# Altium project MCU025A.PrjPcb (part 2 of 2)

## Sheet MCU025A_XDS110_MCU.SchDoc
size 431 x 279 mm; Date: Not shown in title block; ApprovedBy: Not shown in title block; CheckedBy: Not shown in title block; Author: Not shown in title block; CompanyName: Not shown in title block; Engineer: Not shown in title block; Organization: Not shown in title block; Address1: Not shown in title block; Address2: Not shown in title block; Address3: Not shown in title block; Address4: Not shown in title block; DocumentNumber: 7; Revision: Use project parameter SCH_Rev; SheetNumber: 7; SheetTotal: 8; PageSetup: Record=PageOptions¦CenterHorizontal=True¦CenterVertical=True¦PrintScale=1.00¦XCorrection=1.00¦YCorrection=1.00¦PrintKind=0¦BorderSize=5000000¦LeftOffset=0¦BottomOffset=0¦Orientation=2¦PaperLength=1000¦PaperWidth=1000¦Scale=100¦PaperSource=15¦PrintQuality=600¦MediaType=1¦DitherType=10¦PaperKind=Letter¦PrintScaleMode=1

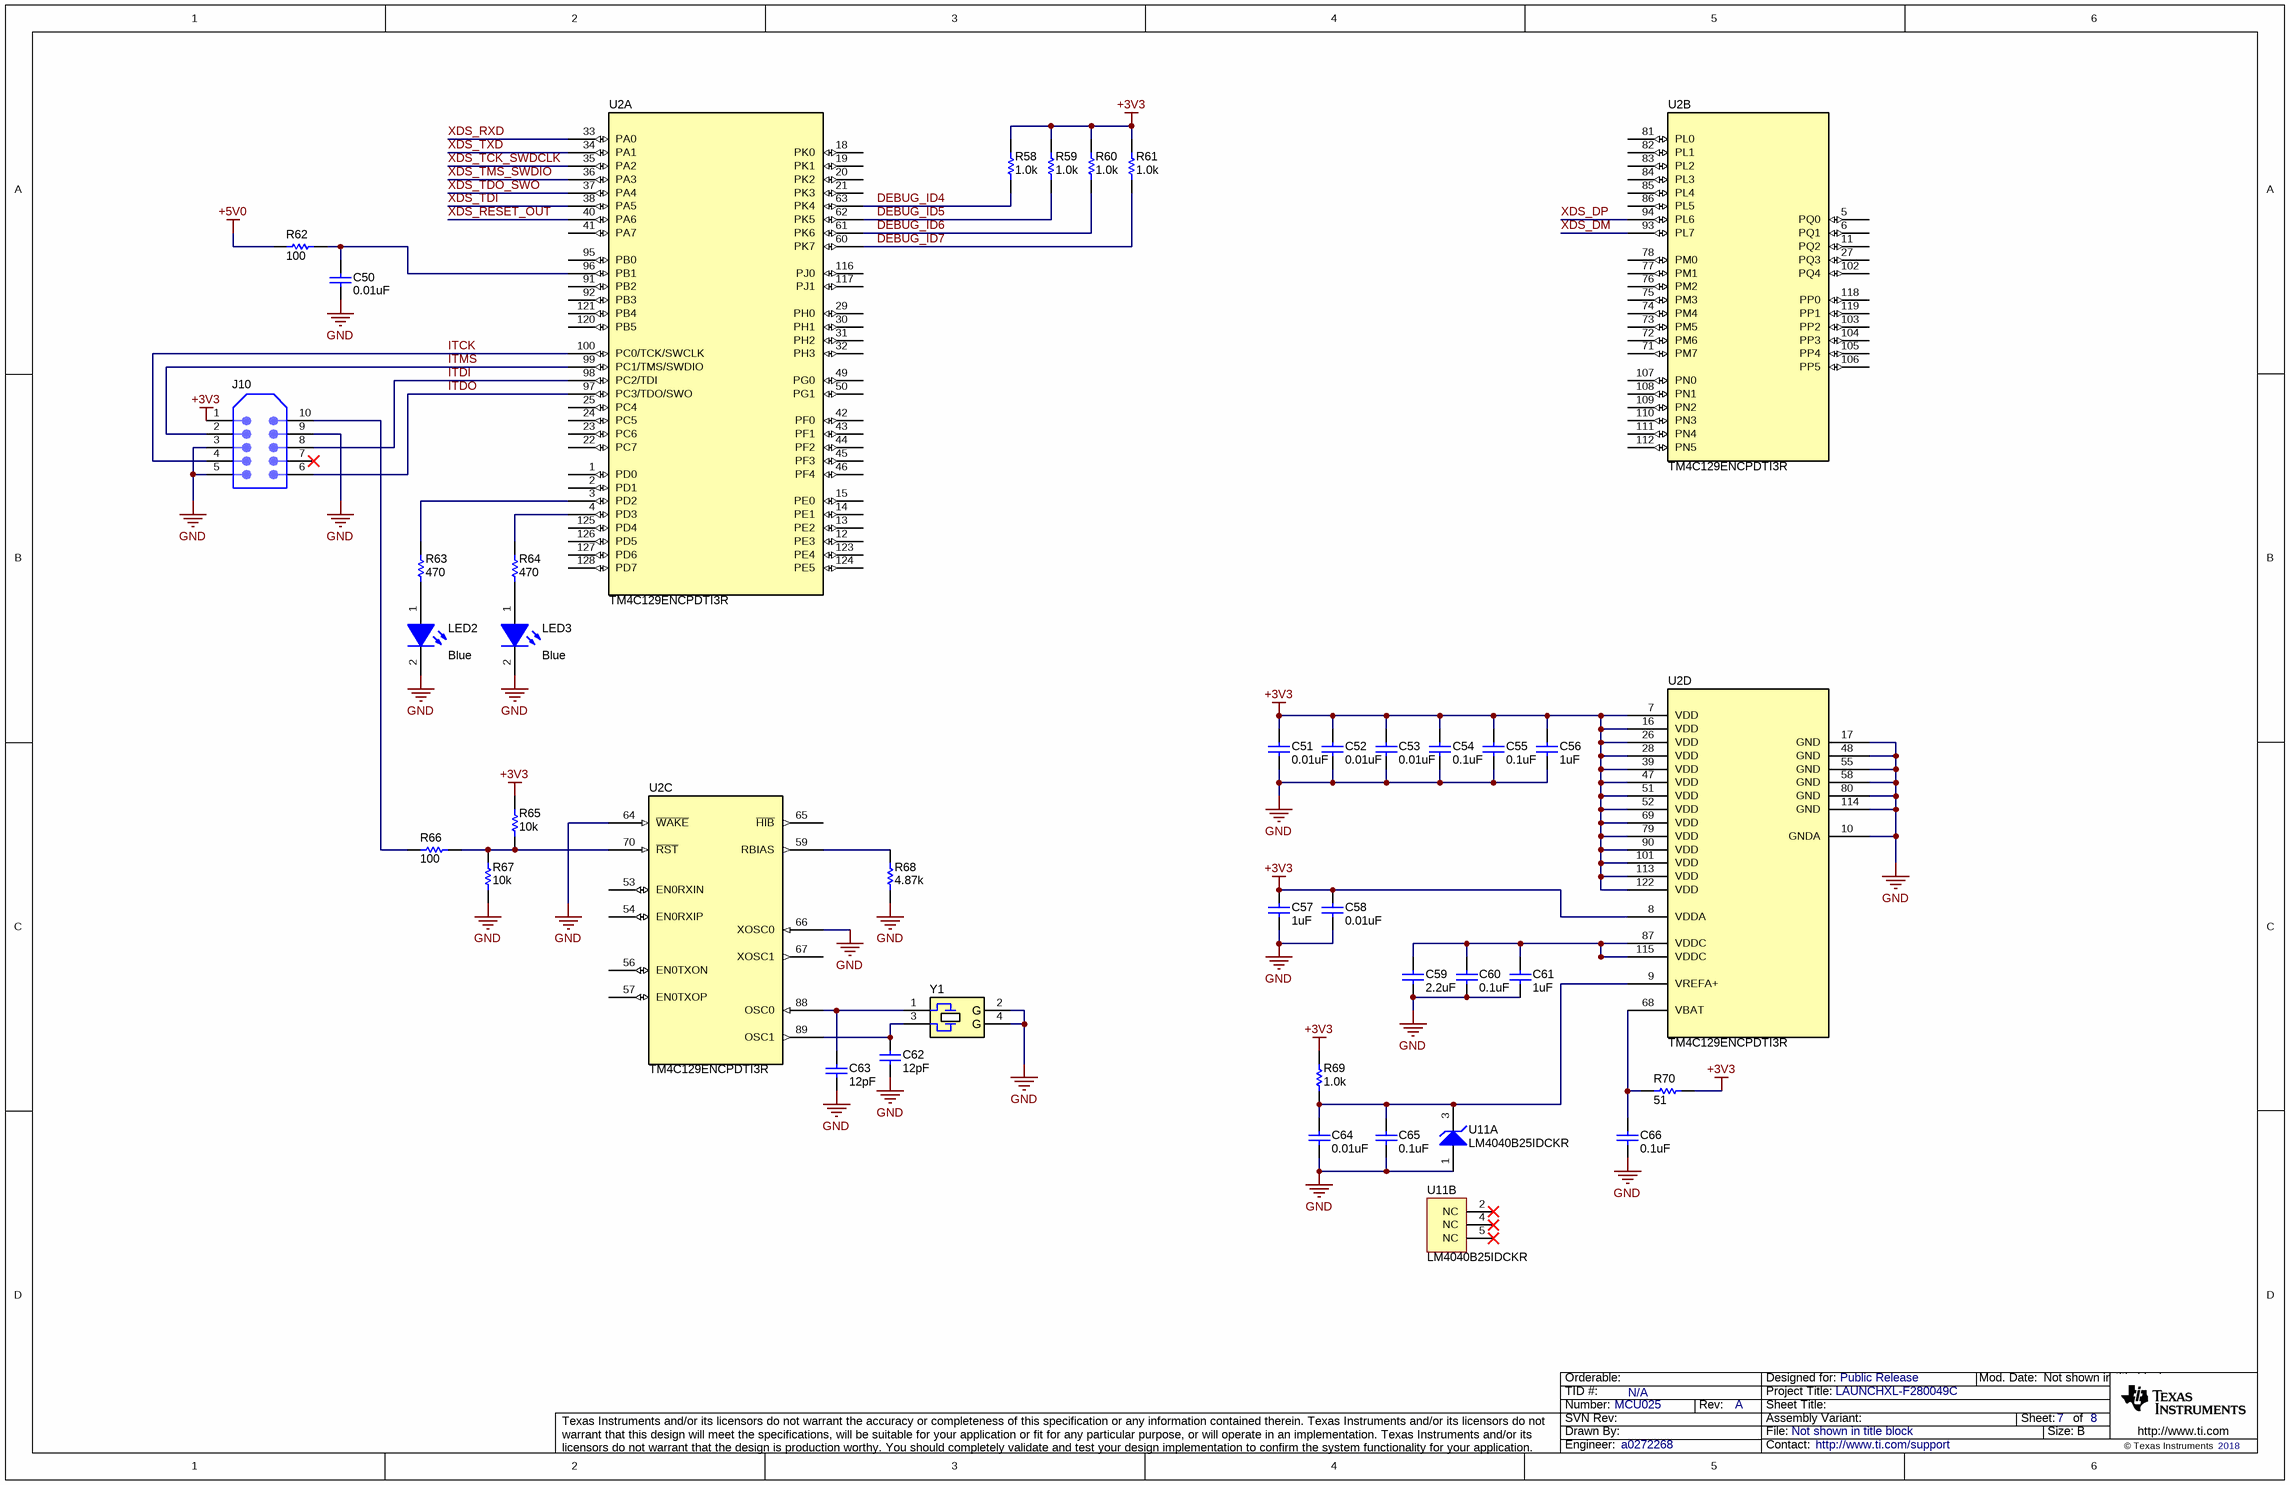
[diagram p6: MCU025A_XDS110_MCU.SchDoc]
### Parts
C50  ValueDisplayed: 0.01uF  [0402]  (hidden comment: GRM155R71E103KA01D)
C51  ValueDisplayed: 0.01uF  [0402]  (hidden comment: GRM155R71E103KA01D)
C52  ValueDisplayed: 0.01uF  [0402]  (hidden comment: GRM155R71E103KA01D)
C53  ValueDisplayed: 0.01uF  [0402]  (hidden comment: GRM155R71E103KA01D)
C54  ValueDisplayed: 0.1uF  [0402]  (hidden comment: GRM155R70J104KA01D)
C55  ValueDisplayed: 0.1uF  [0402]  (hidden comment: GRM155R70J104KA01D)
C56  ValueDisplayed: 1uF  [0402]  (hidden comment: GRM155R61A105KE15D)
C57  ValueDisplayed: 1uF  [0402]  (hidden comment: GRM155R61A105KE15D)
C58  ValueDisplayed: 0.01uF  [0402]  (hidden comment: GRM155R71E103KA01D)
C59  ValueDisplayed: 2.2uF  [0402]  (hidden comment: GRM155R60J225KE95D)
C60  ValueDisplayed: 0.1uF  [0402]  (hidden comment: GRM155R70J104KA01D)
C61  ValueDisplayed: 1uF  [0402]  (hidden comment: GRM155R61A105KE15D)
C62  ValueDisplayed: 12pF  [0402]  (hidden comment: GRM1555C1H120JA01D)
C63  ValueDisplayed: 12pF  [0402]  (hidden comment: GRM1555C1H120JA01D)
C64  ValueDisplayed: 0.01uF  [0402]  (hidden comment: GRM155R71E103KA01D)
C65  ValueDisplayed: 0.1uF  [0402]  (hidden comment: GRM155R70J104KA01D)
C66  ValueDisplayed: 0.1uF  [0402]  (hidden comment: GRM155R70J104KA01D)
J10  TC2050-IDC-NL-FP  [Tag_TC2050-NL]  (value not drawn)  (no BOM)
LED2  value Blue  [LTST-C170TBKT_Blue]  (hidden comment: LTST-C170TBKT)
LED3  value Blue  [LTST-C170TBKT_Blue]  (hidden comment: LTST-C170TBKT)
R58  ValueDisplayed: 1.0k  [0402]  (hidden comment: CRCW04021K00JNED)
R59  ValueDisplayed: 1.0k  [0402]  (hidden comment: CRCW04021K00JNED)
R60  ValueDisplayed: 1.0k  [0402]  (hidden comment: CRCW04021K00JNED)
R61  ValueDisplayed: 1.0k  [0402]  (hidden comment: CRCW04021K00JNED)
R62  ValueDisplayed: 100  [0402]  (hidden comment: CRCW0402100RJNED)
R63  ValueDisplayed: 470  [0402]  (hidden comment: ERJ-2RKF4700X)
R64  ValueDisplayed: 470  [0402]  (hidden comment: ERJ-2RKF4700X)
R65  ValueDisplayed: 10k  [0402]  (hidden comment: CRCW040210K0JNED)
R66  ValueDisplayed: 100  [0402]  (hidden comment: CRCW0402100RJNED)
R67  ValueDisplayed: 10k  [0402]  (hidden comment: CRCW040210K0JNED)
R68  ValueDisplayed: 4.87k  [0402]  (hidden comment: CRCW04024K87FKED)
R69  ValueDisplayed: 1.0k  [0402]  (hidden comment: CRCW04021K00JNED)
R70  ValueDisplayed: 51  [0402]  (hidden comment: CRCW040251R0JNED)
U2  TM4C129ENCPDTI3R  [PDT0128A]  (parts A,B,C,D of 4)
U11  LM4040B25IDCKR  [DCK0005A_N]  (parts A,B of 2)
Y1  NX3225GA-16.000M-STD-CRG-1  [NDK_NX3225GA]  (value not drawn)

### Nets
+3V3: C51.1 C52.1 C53.1 C54.1 C55.1 C56.1 C57.1 C58.1 J10.1 R58.2 R59.2 R60.2 R61.2 R65.2 R69.2 R70.2 U2.7(VDD) U2.8(VDDA) U2.16(VDD) U2.26(VDD) U2.28(VDD) U2.39(VDD) U2.47(VDD) U2.51(VDD) U2.52(VDD) U2.69(VDD) U2.79(VDD) U2.90(VDD) U2.101(VDD) U2.113(VDD) U2.122(VDD)
+5V0: R62.1
GND: C50.2 C51.2 C52.2 C53.2 C54.2 C55.2 C56.2 C57.2 C58.2 C59.2 C60.2 C61.2 C62.2 C63.2 C64.2 C65.2 C66.2 J10.3 J10.5 J10.9 LED2.2(K) LED3.2(K) R67.1 R68.1 U2.10(GNDA) U2.17(GND) U2.48(GND) U2.55(GND) U2.58(GND) U2.64(~{WAKE}) U2.66(XOSC0) U2.80(GND) U2.114(GND) U11.1(ANODE) Y1.2(GND) Y1.4(GND)
DEBUG_ID4: R58.1 U2.63(PK4)
DEBUG_ID5: R59.1 U2.62(PK5)
DEBUG_ID6: R60.1 U2.61(PK6)
DEBUG_ID7: R61.1 U2.60(PK7)
ITCK: J10.4 U2.100(PC0/TCK/SWCLK)
ITDI: J10.8 U2.98(PC2/TDI)
ITDO: J10.6 U2.97(PC3/TDO/SWO)
ITMS: J10.2 U2.99(PC1/TMS/SWDIO)
XDS_DM: U2.93(PL7)
XDS_DP: U2.94(PL6)
XDS_RESET_OUT: U2.40(PA6)
XDS_RXD: U2.33(PA0)
XDS_TCK_SWDCLK: U2.35(PA2)
XDS_TDI: U2.38(PA5)
XDS_TDO_SWO: U2.37(PA4)
XDS_TMS_SWDIO: U2.36(PA3)
XDS_TXD: U2.34(PA1)
NetC50_1: C50.1 R62.2 U2.96(PB1)
NetC59_1: C59.1 C60.1 C61.1 U2.87(VDDC) U2.115(VDDC)
NetC62_1: C62.1 U2.89(OSC1) Y1.3
NetC63_1: C63.1 U2.88(OSC0) Y1.1
NetC64_1: C64.1 C65.1 R69.1 U2.9(VREFA+) U11.3(CATHODE)
NetC66_1: C66.1 R70.1 U2.68(VBAT)
NetJ10_10: J10.10 R66.1
NetLED2_1: LED2.1(A) R63.1
NetLED3_1: LED3.1(A) R64.1
NetR63_2: R63.2 U2.3(PD2)
NetR64_2: R64.2 U2.4(PD3)
NetR65_1: R65.1 R66.2 R67.2 U2.70(~{RST})
NetR68_2: R68.2 U2.59(RBIAS)

Not connected (* = marked no-connect by the designer): J10 7*; U2 1(PD0) 2(PD1) 5(PQ0) 6(PQ1) 11(PQ2) 12(PE3) 13(PE2) 14(PE1) 15(PE0) 18(PK0) 19(PK1) 20(PK2) 21(PK3) 22(PC7) 23(PC6) 24(PC5) 25(PC4) 27(PQ3) 29(PH0) 30(PH1) 31(PH2) 32(PH3) 41(PA7) 42(PF0) 43(PF1) 44(PF2) 45(PF3) 46(PF4) 49(PG0) 50(PG1) 53(EN0RXIN) 54(EN0RXIP) 56(EN0TXON) 57(EN0TXOP) 65(~{HIB}) 67(XOSC1) 71(PM7) 72(PM6) 73(PM5) 74(PM4) 75(PM3) 76(PM2) 77(PM1) 78(PM0) 81(PL0) 82(PL1) 83(PL2) 84(PL3) 85(PL4) 86(PL5) 91(PB2) 92(PB3) 95(PB0) 102(PQ4) 103(PP2) 104(PP3) 105(PP4) 106(PP5) 107(PN0) 108(PN1) 109(PN2) 110(PN3) 111(PN4) 112(PN5) 116(PJ0) 117(PJ1) 118(PP0) 119(PP1) 120(PB5) 121(PB4) 123(PE4) 124(PE5) 125(PD4) 126(PD5) 127(PD6) 128(PD7); U11 2(NC)* 4(NC)* 5(NC)*

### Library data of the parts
C50-C53 C58 C64 = CMP-0006658-2: CAP, CERM, 0.01 uF, 25 V, +/- 10%, X7R, 0402; Manufacturer: MuRata; Polarized: N; Value: 0.01uF; U/M: EA; Cap_F: 10nF; Value1: Unknown; VDC_V: 25V; TaMin_C: -55°C; TaMax_C: 125°C; SizeArea_mm2: 0.5; SizeAreaWB_mm2: 3; SizeX_mm: 1; SizeZ_mm: 0.6; AEC Category: Q200
C54 C55 C60 C65 C66 = CMP-0006623-2: CAP, CERM, 0.1 uF, 6.3 V, +/- 10%, X7R, 0402; Manufacturer: MuRata; Polarized: N; Value: 0.1uF; U/M: EA; Cap_F: 100nF; Value1: Unknown; VDC_V: 6.3V; TaMin_C: -55°C; TaMax_C: 125°C; SizeArea_mm2: 0.5; SizeAreaWB_mm2: 3; SizeX_mm: 1; SizeZ_mm: 0.6; AEC Category: Q200
C56 C57 C61 = CMP-0006563-2: CAP, CERM, 1 uF, 10 V, +/- 10%, X5R, 0402; Manufacturer: MuRata; Polarized: N; Value: 1uF; U/M: EA; Cap_F: 1µF; Value1: Unknown; VDC_V: 10V; TaMin_C: -55°C; TaMax_C: 85°C; SizeArea_mm2: 0.5; SizeAreaWB_mm2: 3; SizeX_mm: 1; SizeZ_mm: 0.6; AEC Category: Q200
C59 = CMP-0006543-2: CAP, CERM, 2.2 uF, 6.3 V, +/- 10%, X5R, 0402; Manufacturer: MuRata; Polarized: N; Value: 2.2uF; U/M: EA; Cap_F: 2.2µF; Value1: Unknown; VDC_V: 6.3V; TaMin_C: -55°C; TaMax_C: 85°C; SizeArea_mm2: 0.5; SizeAreaWB_mm2: 3; SizeX_mm: 1; SizeZ_mm: 0.6; AEC Category: Q200
C62 C63 = CMP-0006415-2: CAP, CERM, 12 pF, 50 V, +/- 5%, C0G/NP0, 0402; Manufacturer: MuRata; Polarized: N; Value: 12pF; U/M: EA; Value1: Unknown; VDC_V: 50V; TaMin_C: -55°C; TaMax_C: 125°C; SizeArea_mm2: 0.5; SizeAreaWB_mm2: 3; SizeX_mm: 1; SizeZ_mm: 0.6; AEC Category: Q200
J10 = CMP-0075101-1: Footprint for Tag-Connect TC2050 No-Legs cables; CompType: Receptacle; Note: Footprint only, to mate with Tag-Connect TC2050 No-Legs cables; CNHeader: False
LED2 LED3 = CMP-0002889-1: LED, Blue, SMD; Manufacturer: Lite-On; Type: AlInGaP; Vf_V: 3.3V; Io_A: 20mA; Value1: W; U/M: EA
R58-R61 = CMP-0026852-3: RES, 1.0 k, 5%, 0.063 W, AEC-Q200 Grade 0, 0402; Manufacturer: Vishay-Dale; Power_W: 63mW; TempCo: 200 ppm/C; Value_Code: 1k00; Value: 1.0k; EIA_Code: E24; Res_ohm: 1k; SizeX_mm: 1; SizeY_mm: 0.5; SizeZ_mm: 0.6; Value2: 0.063W; AEC Qualified: Y; VDC_V: 50V; AEC Category: Q200; AEC Grade: 0
R62 R66 = CMP-0026824-3: RES, 100, 5%, 0.063 W, AEC-Q200 Grade 0, 0402; Manufacturer: Vishay-Dale; Value: 100; Value_Code: 100R; Power_W: 63mW; Value2: 0.063W; VDC_V: 50V; TempCo: 200 ppm/C; SizeArea_mm2: 0.5; SizeX_mm: 1; SizeZ_mm: 0.6; EIA_Code: E24; AEC Category: Q200; AEC Qualified: Y; AEC Grade: 0
R63 R64 = CMP-0026699-1: RES, 470, 1%, 0.1 W, AEC-Q200 Grade 0, 0402; Manufacturer: Panasonic; Value: 470; Value_Code: 470R; Power_W: 100mW; Value2: 0.1W; VDC_V: 50V; TempCo: 100 ppm/C; SizeArea_mm2: 0.5; SizeX_mm: 1; SizeZ_mm: 0.6; U/M: EA; AEC Category: Q200; AEC Qualified: Y; AEC Grade: 0
R65 R67 = CMP-0026825-5: RES, 10 k, 5%, 0.063 W, AEC-Q200 Grade 0, 0402; Manufacturer: Vishay-Dale; Value: 10k; Value_Code: 10k0; Power_W: 63mW; Value2: 0.063W; VDC_V: 50V; TempCo: 200 ppm/C; SizeArea_mm2: 0.5; SizeX_mm: 1; SizeZ_mm: 0.6; EIA_Code: E24; AEC Category: Q200; AEC Qualified: Y; AEC Grade: 0
R68 = CMP-0026413-2: RES, 4.87 k, 1%, 0.063 W, AEC-Q200 Grade 0, 0402; Manufacturer: Vishay-Dale; Value: 4.87k; Value_Code: 4k87; Power_W: 63mW; Value2: 0.063W; VDC_V: 50V; TempCo: 100 ppm/C; SizeArea_mm2: 0.5; SizeX_mm: 1; SizeZ_mm: 0.6; EIA_Code: E96; AEC Category: Q200; AEC Qualified: Y; AEC Grade: 0
R69 = CMP-0026852-3: RES, 1.0 k, 5%, 0.063 W, AEC-Q200 Grade 0, 0402; Manufacturer: Vishay-Dale; Value: 1.0k; Res_ohm: 1k; Value_Code: 1k00; Power_W: 63mW; Value2: 0.063W; VDC_V: 50V; TempCo: 200 ppm/C; SizeArea_mm2: 0.5; SizeX_mm: 1; SizeZ_mm: 0.6; EIA_Code: E24; AEC Category: Q200; AEC Qualified: Y; AEC Grade: 0
R70 = CMP-0026946-3: RES, 51, 5%, 0.063 W, AEC-Q200 Grade 0, 0402; Manufacturer: Vishay-Dale; Value: 51; Value_Code: 51R0; Power_W: 63mW; Value2: 0.063W; VDC_V: 50V; TempCo: 200 ppm/C; SizeArea_mm2: 0.5; SizeX_mm: 1; SizeZ_mm: 0.6; EIA_Code: E24; AEC Category: Q200; AEC Qualified: Y; AEC Grade: 0
U2 = CMP-0067512-2: IoT enabled High performance 32-bit ARM(R) Cortex(R)-M4F based MCU, PDT0128A (TQFP-128); Manufacturer: Texas Instruments; SizeArea_mm2: 256.0; SizeAreaWB_mm2: 324.0; SizeX_mm: 16.0; SizeZ_mm: 1.2; CompType: IC; U/M: EA
U11 = CMP-0032785-2: Precision Micropower Shunt Voltage Reference, 0.2% accuracy, 2.5 V, 15 ppm / degC, 15 mA, -40 to 85 degC, 5-pin SC70 (DCK), Green (RoHS & no Sb/Br); Manufacturer: Texas Instruments; Iout/Iz(Max)(mA): 15; Temp Coeff(Max)(ppm/ degree C): 100; VO(V): 2.5; Min Iz for Regulation(uA): 75; Initial Accuracy @ 25/deg C(%): 0.2; Rating: Catalog; AEC Category: Q200; AEC Qualified: N; CompType: IC; SizeArea_mm2: 4.2; SizeAreaWB_mm2: 9.3; SizeX_mm: 2.1; SizeY_mm: 2.0; SizeZ_mm: 1.1
Y1 = CMP-0004635-3: Crystal, 16 MHz, 8pF, SMD; Manufacturer: NDK; TaMin_C: -10°C; TaMax_C: 70°C; Frequency Stability: +/-30ppm; Frequency_Fixed: 16MHz

## Sheet MCU025A_Hardware.SchDoc
size 431 x 279 mm; Date: Not shown in title block; ApprovedBy: Not shown in title block; CheckedBy: Not shown in title block; Author: Not shown in title block; CompanyName: Not shown in title block; Engineer: Not shown in title block; Organization: Not shown in title block; Address1: Not shown in title block; Address2: Not shown in title block; Address3: Not shown in title block; Address4: Not shown in title block; DocumentNumber: 8; Revision: Use project parameter SCH_Rev; SheetNumber: 8; SheetTotal: 8; PageSetup: Record=PageOptions¦CenterHorizontal=True¦CenterVertical=True¦PrintScale=1.00¦XCorrection=1.00¦YCorrection=1.00¦PrintKind=0¦BorderSize=5000000¦LeftOffset=0¦BottomOffset=0¦Orientation=2¦PaperLength=1000¦PaperWidth=1000¦Scale=100¦PaperSource=15¦PrintQuality=600¦MediaType=1¦DitherType=10¦PaperKind=Letter¦PrintScaleMode=1

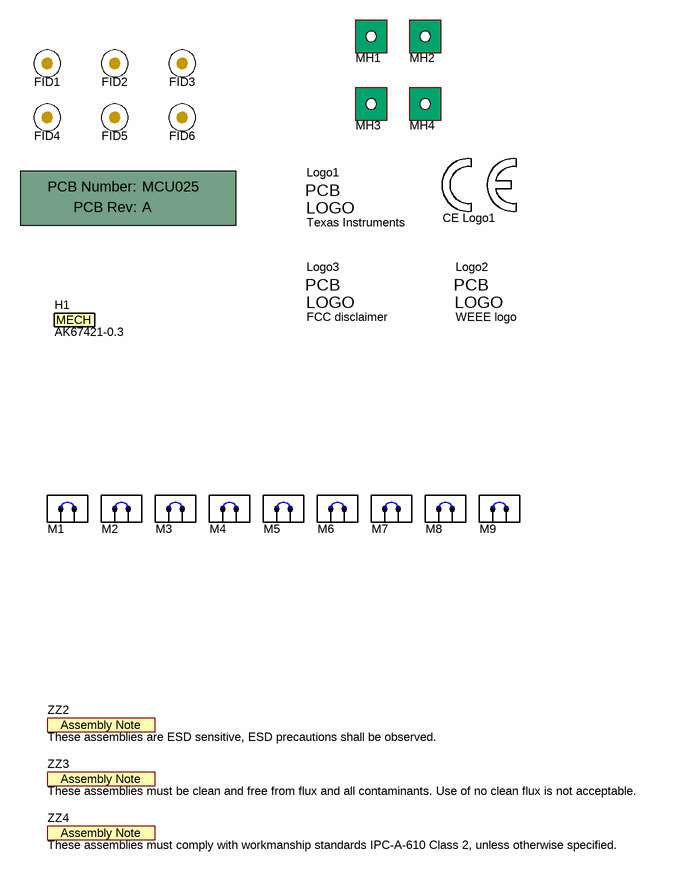
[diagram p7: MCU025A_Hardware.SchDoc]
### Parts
!PCB1  Printed Circuit Board  (value not drawn)  (mechanical)
CE_Logo1  CE Mark  [CE_Mark_5mm]  (value not drawn)  (no BOM)
FID1  Fiducial  [Fiducial10-20]  (value not drawn)  (no BOM)
FID2  Fiducial  [Fiducial10-20]  (value not drawn)  (no BOM)
FID3  Fiducial  [Fiducial10-20]  (value not drawn)  (no BOM)
FID4  Fiducial  [Fiducial10-20]  (value not drawn)  (no BOM)
FID5  Fiducial  [Fiducial10-20]  (value not drawn)  (no BOM)
FID6  Fiducial  [Fiducial10-20]  (value not drawn)  (no BOM)
H1  AK67421-0.3  (mechanical)
Logo1  Texas Instruments  [TI_Stacked_Overlay_Small]  (no BOM)
Logo2  WEEE logo  [WEEE_Minimum]  (no BOM)
Logo3  FCC disclaimer  [FCC_disclaimer]  (no BOM)
M1  60900213421  [Wurth_60900213421]  (value not drawn)
M2  60900213421  [Wurth_60900213421]  (value not drawn)
M3  60900213421  [Wurth_60900213421]  (value not drawn)
M4  60900213421  [Wurth_60900213421]  (value not drawn)
M5  60900213421  [Wurth_60900213421]  (value not drawn)
M6  60900213421  [Wurth_60900213421]  (value not drawn)
M7  60900213421  [Wurth_60900213421]  (value not drawn)
M8  60900213421  [Wurth_60900213421]  (value not drawn)
M9  60900213421  [Wurth_60900213421]  (value not drawn)
MH1  MTG_NoPads  [NPTH125mil]  (value not drawn)  (no BOM)
MH2  MTG_NoPads  [NPTH125mil]  (value not drawn)  (no BOM)
MH3  MTG_NoPads  [NPTH125mil]  (value not drawn)  (no BOM)
MH4  MTG_NoPads  [NPTH125mil]  (value not drawn)  (no BOM)
ZZ2  These assemblies are ESD sensitive, ESD precautions shall be observed.  [AssemblyNote]  (no BOM)
ZZ3  These assemblies must be clean and free from flux and all contaminants. Use of no clean flux is not acceptable.  [AssemblyNote]  (no BOM)
ZZ4  These assemblies must comply with workmanship standards IPC-A-610 Class 2, unless otherwise specified.  [AssemblyNote]  (no BOM)

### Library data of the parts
!PCB1 = CMP-0003618-2: Manufacturer: Any; PartNumber: MCU025
CE_Logo1 = CMP-0074844-1: SymbolCreator: a0412235
FID1-FID6 = CMP-0077181-1: Fiducial mark.  There is nothing to buy or mount.
H1 = CMP-0077983-1: Cable, USB-A to micro USB-B, 0.3 m; Manufacturer: Assman WSW
Logo1 = CMP-0074838-1: Texas Instrument Corporate Signature; SymbolCreator: a0412235; Lib Reference: TI_Logo; Library Reference: Logo
Logo2 = CMP-0074769-1
Logo3 = CMP-0074847-1: FCC_disclaimer; Library Reference: Logo
M1-M9 = CMP-0003761-2: Shunt, 2.54mm, Gold, Black; Manufacturer: Wurth Elektronik
MH1-MH4 = CMP-0078424-2: PCB Mounting Hole, No Pad; Manufacturer: Any; Key: Mounting Hole (non-standard) No Pad
ZZ2 = CMP-0077236-1
ZZ3 = CMP-0077237-1
ZZ4 = CMP-0077238-1

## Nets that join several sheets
+3V3: MCU025A_Connectors (5 pins), MCU025A_AltRouting_Misc (16 pins), MCU025A_F280049C_Device (6 pins), MCU025A_XDS110_Target_Interface (J102.1 R57.2 U12.8), MCU025A_XDS110_USB_Power (21 pins), MCU025A_XDS110_MCU (31 pins)
+5V0: MCU025A_Connectors (10 pins), MCU025A_AltRouting_Misc (C42.2 U7.15), MCU025A_XDS110_USB_Power (5 pins), MCU025A_XDS110_MCU (R62.1)
GND: MCU025A_Connectors (20 pins), MCU025A_AltRouting_Misc (25 pins), MCU025A_F280049C_Device (42 pins), MCU025A_XDS110_Target_Interface (J102.3 J102.5 J102.9 U12.4), MCU025A_XDS110_USB_Power (24 pins), MCU025A_XDS110_MCU (36 pins)
VDD: MCU025A_F280049C_Device (10 pins), MCU025A_XDS110_USB_Power (TP1.1)
VDDA: MCU025A_F280049C_Device (6 pins), MCU025A_XDS110_USB_Power (TP3.1)
VDDIO: MCU025A_F280049C_Device (12 pins), MCU025A_XDS110_USB_Power (TP2.1)
ADCINA0: MCU025A_Connectors (J5.30), MCU025A_F280049C_Device (R13.1)
ADCINA1: MCU025A_Connectors (J1.30), MCU025A_F280049C_Device (R15.1)
ADCINA2: MCU025A_Connectors (J5.24), MCU025A_F280049C_Device (U1.9)
ADCINA3_P2I: MCU025A_Connectors (J5.29), MCU025A_F280049C_Device (R16.2 U1.10)
ADCINA4_P2OF: MCU025A_Connectors (J5.6), MCU025A_F280049C_Device (R19.1)
ADCINA5: MCU025A_Connectors (J1.23), MCU025A_F280049C_Device (U1.35)
ADCINA6: MCU025A_Connectors (J5.23), MCU025A_F280049C_Device (U1.6)
ADCINA8_P6OF: MCU025A_Connectors (J5.8), MCU025A_F280049C_Device (R22.1)
ADCINA9_P5I: MCU025A_Connectors (J1.29), MCU025A_F280049C_Device (R20.2 U1.38)
ADCINB0: MCU025A_Connectors (J1.24), MCU025A_F280049C_Device (U1.41)
ADCINB1: MCU025A_Connectors (J1.26), MCU025A_F280049C_Device (U1.40)
ADCINB2_P1I: MCU025A_Connectors (J1.27), MCU025A_F280049C_Device (R14.2 U1.7)
ADCINB3: MCU025A_Connectors (J1.6), MCU025A_F280049C_Device (U1.8)
ADCINB4_P4OF: MCU025A_Connectors (J5.5), MCU025A_F280049C_Device (R25.1)
ADCINC0_P3I: MCU025A_Connectors (J1.28), MCU025A_F280049C_Device (R17.2 U1.19)
ADCINC1: MCU025A_Connectors (J5.26), MCU025A_F280049C_Device (U1.29)
ADCINC2: MCU025A_Connectors (J1.25), MCU025A_F280049C_Device (U1.21)
ADCINC3_P4I: MCU025A_Connectors (J5.27), MCU025A_F280049C_Device (R18.2)
ADCINC4: MCU025A_Connectors (J1.8), MCU025A_F280049C_Device (U1.17)
ADCINC5_P6I: MCU025A_Connectors (J5.28), MCU025A_F280049C_Device (R21.2)
ADCINC14: MCU025A_Connectors (J5.25), MCU025A_F280049C_Device (U1.44)
EQEP1A: MCU025A_Connectors (C43.1 J12.1 R48.1), MCU025A_AltRouting_Misc (U7.16)
EQEP1B: MCU025A_Connectors (C44.1 J12.2 R49.1), MCU025A_AltRouting_Misc (U7.14)
EQEP1I: MCU025A_Connectors (C45.1 J12.3 R50.1), MCU025A_AltRouting_Misc (U7.13)
EQEP2A: MCU025A_Connectors (C46.1 J13.1 R51.1), MCU025A_AltRouting_Misc (U7.12)
EQEP2B: MCU025A_Connectors (C47.1 J13.2 R52.1), MCU025A_AltRouting_Misc (U7.11)
EQEP2I: MCU025A_Connectors (C48.1 J13.3 R53.1), MCU025A_AltRouting_Misc (U7.10)
GPIO0: MCU025A_Connectors (J6.40), MCU025A_F280049C_Device (U1.79)
GPIO1: MCU025A_Connectors (J6.39), MCU025A_F280049C_Device (U1.78)
GPIO2: MCU025A_Connectors (J6.36), MCU025A_F280049C_Device (U1.77)
GPIO3: MCU025A_Connectors (J6.35), MCU025A_F280049C_Device (U1.76)
GPIO4: MCU025A_Connectors (J2.36), MCU025A_F280049C_Device (U1.75)
GPIO5: MCU025A_Connectors (J2.35), MCU025A_F280049C_Device (U1.89)
GPIO6_BP: MCU025A_Connectors (J6.38), MCU025A_AltRouting_Misc (R44.2)
GPIO6_FSITXDO: MCU025A_Connectors (J11.6), MCU025A_AltRouting_Misc (R44.1), MCU025A_F280049C_Device (U1.97)
GPIO7_BP: MCU025A_Connectors (J6.37), MCU025A_AltRouting_Misc (R45.2)
GPIO7_FSITXCLK: MCU025A_Connectors (J11.2), MCU025A_AltRouting_Misc (R45.1), MCU025A_F280049C_Device (U1.84)
GPIO8: MCU025A_Connectors (J2.38), MCU025A_F280049C_Device (U1.74)
GPIO9: MCU025A_Connectors (J2.37), MCU025A_F280049C_Device (U1.90)
GPIO10: MCU025A_Connectors (J2.40), MCU025A_F280049C_Device (U1.93)
GPIO11: MCU025A_Connectors (J2.39), MCU025A_F280049C_Device (U1.52)
GPIO12_BP: MCU025A_Connectors (J6.11), MCU025A_AltRouting_Misc (R47.2)
GPIO12_FSIRXD0: MCU025A_Connectors (J11.5), MCU025A_AltRouting_Misc (R47.1), MCU025A_F280049C_Device (U1.51)
GPIO13: MCU025A_Connectors (J1.3), MCU025A_F280049C_Device (U1.50)
GPIO14: MCU025A_AltRouting_Misc (U8.14), MCU025A_F280049C_Device (U1.96)
GPIO14_BP: MCU025A_Connectors (J6.32), MCU025A_AltRouting_Misc (U8.13)
GPIO15: MCU025A_AltRouting_Misc (U8.15), MCU025A_F280049C_Device (U1.95)
GPIO15_BP: MCU025A_Connectors (J6.33), MCU025A_AltRouting_Misc (U8.1)
GPIO16: MCU025A_Connectors (J2.15), MCU025A_F280049C_Device (U1.54)
GPIO17: MCU025A_Connectors (J2.14), MCU025A_F280049C_Device (U1.55)
GPIO18_BP: MCU025A_Connectors (J2.32), MCU025A_AltRouting_Misc (R28.1)
GPIO18_X2: MCU025A_AltRouting_Misc (R28.2 R31.2), MCU025A_F280049C_Device (U1.68)
GPIO22: MCU025A_Connectors (J5.7), MCU025A_F280049C_Device (U1.83)
GPIO23: MCU025A_Connectors (J2.12), MCU025A_AltRouting_Misc (R38.1), MCU025A_F280049C_Device (U1.81)
GPIO24: MCU025A_Connectors (J6.15), MCU025A_AltRouting_Misc (R33.1 S2.2), MCU025A_F280049C_Device (U1.56)
GPIO25: MCU025A_Connectors (J2.31), MCU025A_F280049C_Device (U1.57)
GPIO26: MCU025A_AltRouting_Misc (U8.4), MCU025A_F280049C_Device (U1.58)
GPIO26_BP: MCU025A_Connectors (J6.34), MCU025A_AltRouting_Misc (U8.3)
GPIO27: MCU025A_Connectors (J6.19), MCU025A_F280049C_Device (U1.59)
GPIO28: MCU025A_AltRouting_Misc (S6.2), MCU025A_F280049C_Device (U1.1)
GPIO28_BP: MCU025A_Connectors (J5.3), MCU025A_AltRouting_Misc (S6.1)
GPIO29: MCU025A_AltRouting_Misc (S6.5), MCU025A_F280049C_Device (U1.100)
GPIO29_BP: MCU025A_Connectors (J5.4), MCU025A_AltRouting_Misc (S6.4)
GPIO30: MCU025A_Connectors (J2.33), MCU025A_F280049C_Device (U1.98)
GPIO31: MCU025A_Connectors (J6.14), MCU025A_F280049C_Device (U1.99)
GPIO32: MCU025A_AltRouting_Misc (R34.1 S2.1 S9.5), MCU025A_F280049C_Device (U1.64)
GPIO32_BP: MCU025A_Connectors (J6.31), MCU025A_AltRouting_Misc (S9.6)
GPIO32_CANTX: MCU025A_Connectors (U10.1), MCU025A_AltRouting_Misc (S9.4)
GPIO33_BP: MCU025A_Connectors (J6.13), MCU025A_AltRouting_Misc (S9.3)
GPIO33_CANRX: MCU025A_Connectors (U10.4), MCU025A_AltRouting_Misc (S9.1)
GPIO33_FSIRXCLK: MCU025A_Connectors (J11.1), MCU025A_AltRouting_Misc (R46.1), MCU025A_F280049C_Device (U1.53)
GPIO34: MCU025A_Connectors (J6.12), MCU025A_AltRouting_Misc (R39.1), MCU025A_F280049C_Device (U1.94)
GPIO35: MCU025A_AltRouting_Misc (S4.5), MCU025A_F280049C_Device (U1.63)
GPIO35_BP: MCU025A_Connectors (J1.10), MCU025A_AltRouting_Misc (S4.6)
GPIO37: MCU025A_AltRouting_Misc (S4.2), MCU025A_F280049C_Device (U1.61)
GPIO37_BP: MCU025A_Connectors (J1.9), MCU025A_AltRouting_Misc (S4.3)
GPIO39: MCU025A_Connectors (J2.13), MCU025A_F280049C_Device (U1.91)
GPIO40: MCU025A_Connectors (J1.4), MCU025A_F280049C_Device (U1.85)
GPIO56: MCU025A_Connectors (J1.7), MCU025A_F280049C_Device (U1.65)
GPIO57: MCU025A_Connectors (J2.19), MCU025A_F280049C_Device (U1.66)
GPIO58: MCU025A_Connectors (J2.34), MCU025A_F280049C_Device (U1.67)
GPIO59: MCU025A_AltRouting_Misc (U9.4), MCU025A_F280049C_Device (U1.92)
GPIO59_BP: MCU025A_Connectors (J2.11), MCU025A_AltRouting_Misc (U9.3)
PGA135_GND: MCU025A_Connectors (J1.2), MCU025A_F280049C_Device (R23.2)
PGA246_GND: MCU025A_Connectors (J5.2), MCU025A_F280049C_Device (R24.2)
RXD_FROM_XDS: MCU025A_AltRouting_Misc (S8.5), MCU025A_XDS110_Target_Interface (J101.2)
TCK: MCU025A_F280049C_Device (U1.60), MCU025A_XDS110_Target_Interface (J101.8)
TMS: MCU025A_F280049C_Device (R10.1 U1.62), MCU025A_XDS110_Target_Interface (J101.6)
TXD_TO_XDS: MCU025A_AltRouting_Misc (S8.2), MCU025A_XDS110_Target_Interface (J101.4)
X1: MCU025A_AltRouting_Misc (C39.1 R35.1 Y2.3), MCU025A_F280049C_Device (U1.69)
XDS_DM: MCU025A_XDS110_USB_Power (R1.2), MCU025A_XDS110_MCU (U2.93)
XDS_DP: MCU025A_XDS110_USB_Power (R2.2), MCU025A_XDS110_MCU (U2.94)
XDS_RESET_OUT: MCU025A_XDS110_Target_Interface (J102.10 R57.1 U12.2), MCU025A_XDS110_MCU (U2.40)
XDS_RXD: MCU025A_XDS110_Target_Interface (J101.3), MCU025A_XDS110_MCU (U2.33)
XDS_TCK_SWDCLK: MCU025A_XDS110_Target_Interface (J101.7 J102.4 U12.6), MCU025A_XDS110_MCU (U2.35)
XDS_TDI: MCU025A_XDS110_Target_Interface (J102.8 U12.3), MCU025A_XDS110_MCU (U2.38)
XDS_TDO_SWO: MCU025A_XDS110_Target_Interface (J102.6 U12.5), MCU025A_XDS110_MCU (U2.37)
XDS_TMS_SWDIO: MCU025A_XDS110_Target_Interface (J101.5 J102.2 U12.7), MCU025A_XDS110_MCU (U2.36)
XDS_TXD: MCU025A_XDS110_Target_Interface (J101.1), MCU025A_XDS110_MCU (U2.34)
XRSn: MCU025A_Connectors (J2.16 J6.16), MCU025A_AltRouting_Misc (C37.2 R32.1 S1.4), MCU025A_F280049C_Device (U1.2), MCU025A_XDS110_USB_Power (C7.1 R4.1 R5.2)

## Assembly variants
001: not fitted C44 C45 C46 C47 C48 C62 FID1 FID2 FID3 FID4 FID5 FID6 J3 R16 R22 R31 R38 R54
